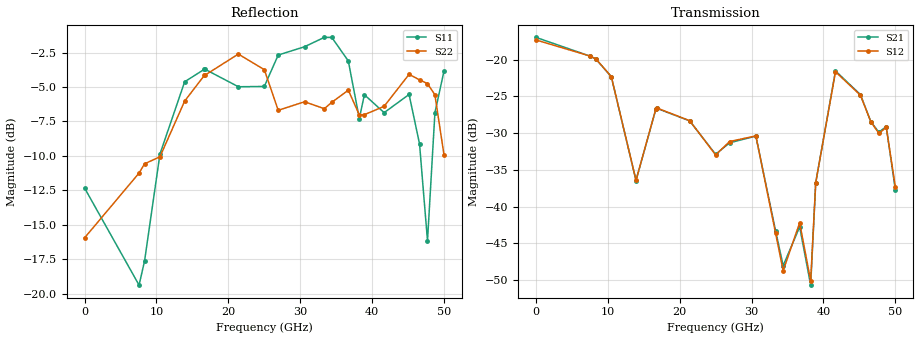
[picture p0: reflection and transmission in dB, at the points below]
!Keysight Technologies,N5245B,MY58422270,A.16.20.02
!Date: Thursday, March 05, 2026 01:16:23
!Correction: S11(C  2-Port  )
!S21(C  2-Port  )
!S12(C  2-Port  )
!S22(C  2-Port  )
!S2P File: Measurements: S11, S21, S12, S22:
# Hz S  dB  R 50
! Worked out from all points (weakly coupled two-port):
!   3201 points, 10 MHz to 50 GHz, reference 50 ohm
!   highest |S21| = -16.94 dB at 10 MHz (marker M1); lowest = -50.7 dB at 38.22 GHz (marker M2)
!   lowest |S11| = -19.4 dB at 7.587 GHz (marker M3), VSWR 1.24, Z = 40.4 - j1.27 ohm
!   |S11| at or under -10 dB: start of sweep to 10.44 GHz; 46.74 GHz to 48.26 GHz (1.518 GHz wide, 3.2 % of centre)
!   |S22| runs from -20.3 to -2.5 dB; largest |S21 - S12| = 0.0063
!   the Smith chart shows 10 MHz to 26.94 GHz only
!   S11 on the Smith chart (normalised r, x): 10 MHz: 1.64, -0.02; 10.49 GHz: 0.53, +0.17; 13.93 GHz: 1.23, +1.60; 16.79 GHz: 1.15, -1.84; 21.4 GHz: 0.31, -0.33; 26.94 GHz: 0.17, +0.36
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1e7  -12.33 -1.4  -16.94 1.9  -17.29 3.1  -15.94 42.6
7.586609e9  -19.37 -171.7  -19.51 41.8  -19.50 41.9  -11.24 -164.6
8.352081e9  -17.62 -164.0  -19.91 7.8  -19.88 7.9  -10.57 177.8
1.049228e10  -9.86 153.3  -22.30 -85.9  -22.29 -86.0  -10.06 109.6
1.392909e10  -4.62 46.1  -36.46 -155.3  -36.42 -155.4  -6.02 -59.6
1.667854e10  -3.71 -41.7  -26.76 159.3  -26.71 159.6  -4.15 -144.4
1.678789e10  -3.72 -44.9  -26.60 155.3  -26.55 155.4  -4.13 -146.5
2.139635e10  -4.98 -140.3  -28.33 14.2  -28.30 14.1  -2.61 132.1
2.5005e10  -4.96 174.7  -32.89 -66.8  -32.97 -67.0  -3.74 70.6
2.694211e10  -2.68 139.2  -31.32 -109.4  -31.14 -109.0  -6.69 37.5
3.059763e10  -2.08 79.5  -30.40 122.9  -30.37 123.8  -6.07 -52.7
3.334708e10  -1.40 35.7  -43.34 0.8  -43.68 -2.5  -6.57 -132.9
3.439375e10  -1.40 17.4  -48.06 -109.9  -48.75 -112.7  -6.11 -156.3
3.669016e10  -3.11 -31.2  -42.79 103.7  -42.23 103.3  -5.23 158.7
3.822111e10  -7.29 -21.8  -50.72 76.7  -50.13 -100.4  -7.02 133.9
3.892409e10  -5.56 -29.8  -36.76 98.8  -36.75 99.8  -7.01 137.0
4.167354e10  -6.86 -55.1  -21.51 -56.6  -21.63 -57.5  -6.40 110.4
4.51416e10  -5.54 -102.0  -24.74 84.1  -24.83 84.4  -4.08 74.0
4.659443e10  -9.12 -153.4  -28.45 30.7  -28.46 31.4  -4.48 53.9
4.770358e10  -16.16 72.0  -29.86 -16.1  -30.02 -16.2  -4.75 41.8
4.873463e10  -6.87 -25.8  -29.10 -89.2  -29.22 -90.1  -5.57 21.0
5e10  -3.84 -72.6  -37.76 -121.9  -37.30 -126.6  -9.92 8.3
